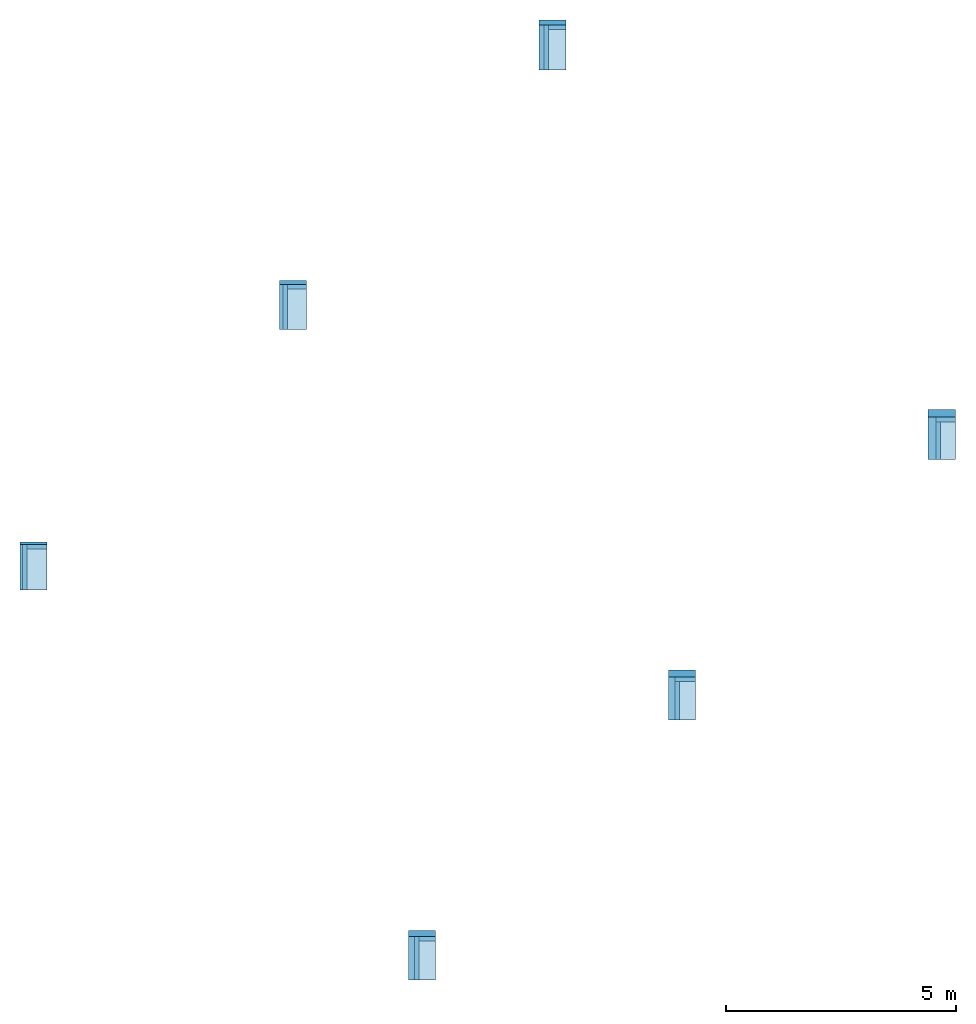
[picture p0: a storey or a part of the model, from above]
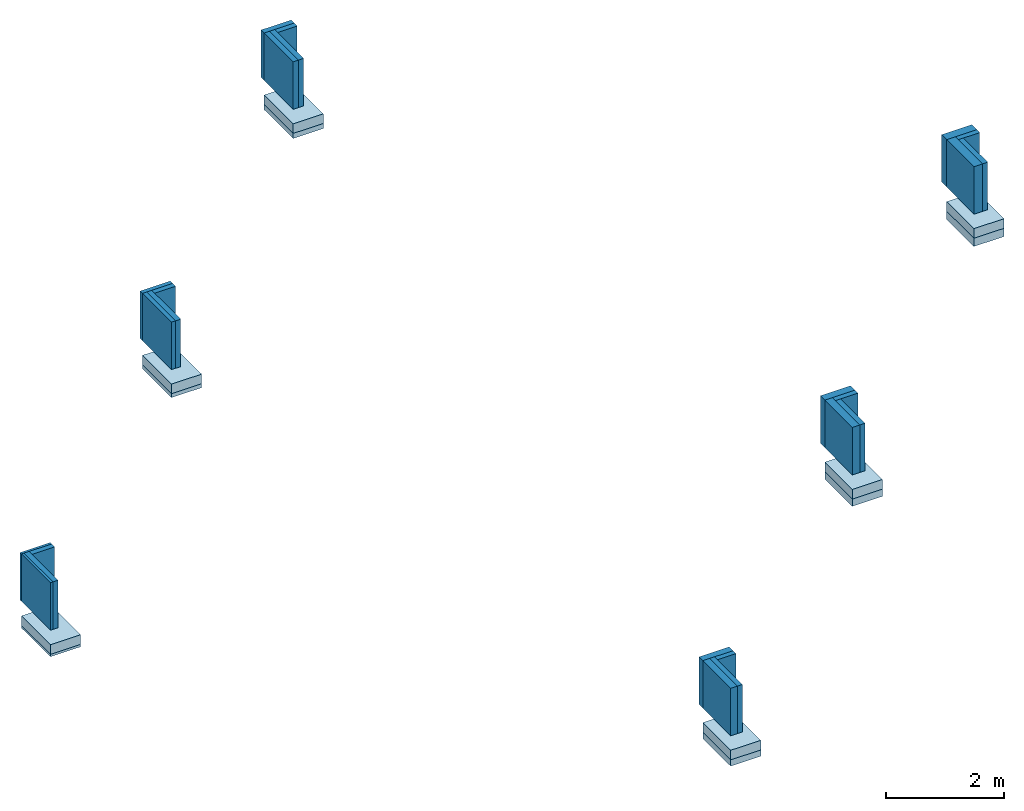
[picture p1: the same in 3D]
Properties of the parts of a building model (IFC2X3), part 1 of 2

# File
Description: ViewDefinition [CoordinationView_V2.0, QuantityTakeOffAddOnView]
File name: 012345
Time: 2019-12-04T13:08:42
Written by: The EXPRESS Data Manager Version 5.02.0100.07 : 28 Aug 2013
Made in: 20190507_1515(x64) - Exporter 17.0.517.0 - Alternate UI 17.15.0.0
Comment: STEP Physical File produced by: The EXPRESS Data Manager Version 5.02.0100.07 : 28 Aug 2013 * Module: EDMstepFileFactory/EDMstandAlone * Creation date: Wed Dec 04 13:08:42 2019 * Host: lt-026 * Database: C:\Users\WF2BF~1.POE\AppData\Local\Temp\{B53F2244-0315-493A-A30E-173DDC3E3202}\ifc * Database version: 5507 * Database creation date: Wed Dec 04 13:08:38 2019 * Schema: IFC2X3 * Model: DataRepository.ifc * Model creation date: Wed Dec 04 13:08:40 2019 * Header model: DataRepository.ifc_HeaderModel * Header model creation date: Wed Dec 04 13:08:40 2019 * EDMuser: sdai-user * EDMgroup: sdai-group * License ID and type: 5605 : Permanent license. Expiry date: * EDMstepFileFactory options: 020000

# IfcProject, 012345
LongName: Cadix Project Naam; Phase: Cadix leeg V2.0

# IfcSite, Default
RefLatitude: 52, 3, 20, 225830; RefLongitude: 5, 6, 28, 692855; RefElevation: 0 mm
Identity Data - Author: Cadix; Organization Name: Cadix
Other - Category: Project Information; Client Name: Vragen? info@cadix.nl; Project Address: Ampèrelaan 1c, 9207 AM Drachten; Project Issue Date: 06-06-2017; Project Name: Cadix Project Naam; Project Number: 012345; Project Status: Cadix leeg V2.0

# IfcBuilding
Pset_BuildingCommon - NumberOfStoreys: 2
Identity Data - Author: Cadix; Organization Name: Cadix
Other - Category: Project Information; Client Name: Vragen? info@cadix.nl; Project Address: Ampèrelaan 1c, 9207 AM Drachten; Project Issue Date: 06-06-2017; Project Name: Cadix Project Naam; Project Number: 012345; Project Status: Cadix leeg V2.0

# IfcBuildingStorey (2)
Dimensions - Computation Height: 0 mm
Identity Data - Structural: no; Building Story: yes; Type Name: niveau
Other - Category: Levels; Family: Level: niveau; Family and Type: Level: niveau; Type: Level: niveau; Type Id: Level: niveau; Family Name: Level
Constraints - Elevation Base: Project Base Point
Graphics - Color: 8421504; Line Pattern: 00_niveau; Line Weight: 1; Symbol: NLRS_00_LAB_niveau bovenkant_gen_cadix: 1.8mm; Symbol at End 1 Default: yes; Symbol at End 2 Default: no
Name | LongName = Name | Elevation (mm) | Constraints, Elevation (mm)
00 begane grond | 00 begane grond | -2.7707e-11 | 0
01 eerste verdieping | 01 eerste verdieping | 985 | 985

# IfcCovering: Compound Ceiling:NLRS_45_CEI_Heraklith Herafoam 105x985x590mm, Compound Ceiling:NLRS_45_CEI_Heraklith Herafoam 105x985x590mm:925877
In: 01 eerste verdieping
PredefinedType: CEILING; Classification: 45.0 (Uniformat); Material: Heraklith® | Herafoam - PIR (0,0215) 55 mm, Heraklith® | Herafoam - PIR (0,0275) 40 mm, Heraklith® | Herafoam - Houtwollaag - 985x590mm 10 mm
Pset_CoveringCommon - Reference: NLRS_45_CEI_Heraklith Herafoam 105x985x590mm; Finish: Heraklith® | Herafoam - Houtwollaag - 985x590mm;; TotalThickness: 105 mm
Pset_ManufacturerTypeInformation - Manufacturer: Knauf Insulation B.V.
BaseQuantities - GrossCeilingArea: 0.58115 m2
Constraints - Room Bounding: yes; Level: Level: 01 eerste verdieping; Height Offset From Level: -105 mm
Dimensions - Area: 0.58115 m2; Perimeter: 3150 mm; Volume: 0.0610207 m3
Other - Category: Ceilings; Family: Compound Ceiling: NLRS_45_CEI_Heraklith Herafoam 105x985x590mm; Family and Type: Compound Ceiling: NLRS_45_CEI_Heraklith Herafoam 105x985x590mm; Type: Compound Ceiling: NLRS_45_CEI_Heraklith Herafoam 105x985x590mm; Type Id: Compound Ceiling: NLRS_45_CEI_Heraklith Herafoam 105x985x590mm; Family Name: Compound Ceiling
Phasing - Phase Created: 1
Analytical Properties - Roughness: 1; Absorptance: 0.1; Heat Transfer Coefficient (U): 0.22577; Thermal mass: 735; Thermal Resistance (R): 4.42929
Construction - Thickness: 105 mm
Graphics - Coarse Scale Fill Color: 0
Identity Data - Type Image: Raster image: Heraklith Herafoam.jpg; Assembly Code: 45.0; brandweerstand: n.v.t; Description: Herafoam - 105mm; DoP: 4010_HERAFOAM; email: customerservice.nl@knaufinsulation.com; geluidsabsorbtie: 0,30; Manufacturer: Knauf Insulation B.V.; Model: Heraklith® | Herafoam is een houtwolcementpaneel gecombineerd met een PIR-plaat.; NLRS_C_Code_Brandklasse: B-s1,d0; NLRS_C_content_creator: Cadix; NLRS_C_content_versie: V1.0; phone: +31(0)162-421245; product URL: https://heraklith.nl/Heraklith-houtwolcementplaten/herafoam; Type Name: NLRS_45_CEI_Heraklith Herafoam 105x985x590mm; URL: www.heraklith.nl; warmteweerstand: 4,10 (m2.K/W)

# IfcCovering: Compound Ceiling:NLRS_45_CEI_Heraklith Herafoam 130x985x590mm, Compound Ceiling:NLRS_45_CEI_Heraklith Herafoam 130x985x590mm:926118
In: 01 eerste verdieping
PredefinedType: CEILING; Classification: 45.0 (Uniformat); Material: Heraklith® | Herafoam - PIR (0,0215) 80 mm, Heraklith® | Herafoam - PIR (0,0275) 40 mm, Heraklith® | Herafoam - Houtwollaag - 985x590mm 10 mm
Pset_CoveringCommon - Reference: NLRS_45_CEI_Heraklith Herafoam 130x985x590mm; Finish: Heraklith® | Herafoam - Houtwollaag - 985x590mm;; TotalThickness: 130 mm
Pset_ManufacturerTypeInformation - Manufacturer: Knauf Insulation B.V.
BaseQuantities - GrossCeilingArea: 0.55755 m2
Constraints - Room Bounding: yes; Level: Level: 01 eerste verdieping; Height Offset From Level: -130 mm
Dimensions - Area: 0.55755 m2; Perimeter: 3070 mm; Volume: 0.0724815 m3
Other - Category: Ceilings; Family: Compound Ceiling: NLRS_45_CEI_Heraklith Herafoam 130x985x590mm; Family and Type: Compound Ceiling: NLRS_45_CEI_Heraklith Herafoam 130x985x590mm; Type: Compound Ceiling: NLRS_45_CEI_Heraklith Herafoam 130x985x590mm; Type Id: Compound Ceiling: NLRS_45_CEI_Heraklith Herafoam 130x985x590mm; Family Name: Compound Ceiling
Phasing - Phase Created: 1
Analytical Properties - Roughness: 1; Absorptance: 0.1; Heat Transfer Coefficient (U): 0.179673; Thermal mass: 810; Thermal Resistance (R): 5.56566
Construction - Thickness: 130 mm
Graphics - Coarse Scale Fill Color: 0
Identity Data - Type Image: Raster image: Heraklith Herafoam.jpg; Assembly Code: 45.0; brandweerstand: n.v.t; Description: Herafoam - 130mm; DoP: 4010_HERAFOAM; email: customerservice.nl@knaufinsulation.com; geluidsabsorbtie: 0,30; Manufacturer: Knauf Insulation B.V.; Model: Heraklith® | Herafoam is een houtwolcementpaneel gecombineerd met een PIR-plaat.; NLRS_C_Code_Brandklasse: B-s1,d0; NLRS_C_content_creator: Cadix; NLRS_C_content_versie: V1.0; phone: +31(0)162-421245; product URL: https://heraklith.nl/Heraklith-houtwolcementplaten/herafoam; Type Name: NLRS_45_CEI_Heraklith Herafoam 130x985x590mm; URL: www.heraklith.nl; warmteweerstand: 5,25 (m2.K/W)

# IfcCovering: Compound Ceiling:NLRS_45_CEI_Heraklith Herafoam 150x985x590mm, Compound Ceiling:NLRS_45_CEI_Heraklith Herafoam 150x985x590mm:926490
In: 01 eerste verdieping
PredefinedType: CEILING; Classification: 45.0 (Uniformat); Material: Heraklith® | Herafoam - PIR (0,0215) 100 mm, Heraklith® | Herafoam - PIR (0,0275) 40 mm, Heraklith® | Herafoam - Houtwollaag - 985x590mm 10 mm
Pset_CoveringCommon - Reference: NLRS_45_CEI_Heraklith Herafoam 150x985x590mm; Finish: Heraklith® | Herafoam - Houtwollaag - 985x590mm;; TotalThickness: 150 mm
Pset_ManufacturerTypeInformation - Manufacturer: Knauf Insulation B.V.
BaseQuantities - GrossCeilingArea: 0.55165 m2
Constraints - Room Bounding: yes; Level: Level: 01 eerste verdieping; Height Offset From Level: -150 mm
Dimensions - Area: 0.55165 m2; Perimeter: 3050 mm; Volume: 0.0827475 m3
Other - Category: Ceilings; Family: Compound Ceiling: NLRS_45_CEI_Heraklith Herafoam 150x985x590mm; Family and Type: Compound Ceiling: NLRS_45_CEI_Heraklith Herafoam 150x985x590mm; Type: Compound Ceiling: NLRS_45_CEI_Heraklith Herafoam 150x985x590mm; Type Id: Compound Ceiling: NLRS_45_CEI_Heraklith Herafoam 150x985x590mm; Family Name: Compound Ceiling
Phasing - Phase Created: 1
Analytical Properties - Roughness: 1; Absorptance: 0.1; Heat Transfer Coefficient (U): 0.154446; Thermal mass: 870; Thermal Resistance (R): 6.47475
Construction - Thickness: 150 mm
Graphics - Coarse Scale Fill Color: 0
Identity Data - Type Image: Raster image: Heraklith Herafoam.jpg; Assembly Code: 45.0; brandweerstand: n.v.t; Description: Herafoam - 150mm; DoP: 4010_HERAFOAM; email: customerservice.nl@knaufinsulation.com; geluidsabsorbtie: 0,30; Manufacturer: Knauf Insulation B.V.; Model: Heraklith® | Herafoam is een houtwolcementpaneel gecombineerd met een PIR-plaat.; NLRS_C_Code_Brandklasse: B-s1,d0; NLRS_C_content_creator: Cadix; NLRS_C_content_versie: V1.0; phone: +31(0)162-421245; product URL: https://heraklith.nl/Heraklith-houtwolcementplaten/herafoam; Type Name: NLRS_45_CEI_Heraklith Herafoam 150x985x590mm; URL: www.heraklith.nl; warmteweerstand: 6,20 (m2.K/W)

# IfcCovering: Compound Ceiling:NLRS_45_CEI_Heraklith Herafoam 170x985x590mm, Compound Ceiling:NLRS_45_CEI_Heraklith Herafoam 170x985x590mm:926819
In: 01 eerste verdieping
PredefinedType: CEILING; Classification: 45.0 (Uniformat); Material: Heraklith® | Herafoam - PIR (0,0215) 120 mm, Heraklith® | Herafoam - PIR (0,0275) 40 mm, Heraklith® | Herafoam - Houtwollaag - 985x590mm 10 mm
Pset_CoveringCommon - Reference: NLRS_45_CEI_Heraklith Herafoam 170x985x590mm; Finish: Heraklith® | Herafoam - Houtwollaag - 985x590mm;; TotalThickness: 170 mm
Pset_ManufacturerTypeInformation - Manufacturer: Knauf Insulation B.V.
BaseQuantities - GrossCeilingArea: 0.54575 m2
Constraints - Room Bounding: yes; Level: Level: 01 eerste verdieping; Height Offset From Level: -170 mm
Dimensions - Area: 0.54575 m2; Perimeter: 3030 mm; Volume: 0.0927775 m3
Other - Category: Ceilings; Family: Compound Ceiling: NLRS_45_CEI_Heraklith Herafoam 170x985x590mm; Family and Type: Compound Ceiling: NLRS_45_CEI_Heraklith Herafoam 170x985x590mm; Type: Compound Ceiling: NLRS_45_CEI_Heraklith Herafoam 170x985x590mm; Type Id: Compound Ceiling: NLRS_45_CEI_Heraklith Herafoam 170x985x590mm; Family Name: Compound Ceiling
Phasing - Phase Created: 1
Analytical Properties - Roughness: 1; Absorptance: 0.1; Heat Transfer Coefficient (U): 0.135431; Thermal mass: 930; Thermal Resistance (R): 7.38384
Construction - Thickness: 170 mm
Graphics - Coarse Scale Fill Color: 0
Identity Data - Type Image: Raster image: Heraklith Herafoam.jpg; Assembly Code: 45.0; brandweerstand: n.v.t; Description: Herafoam - 170mm; DoP: 4010_HERAFOAM; email: customerservice.nl@knaufinsulation.com; geluidsabsorbtie: 0,30; Manufacturer: Knauf Insulation B.V.; Model: Heraklith® | Herafoam is een houtwolcementpaneel gecombineerd met een PIR-plaat.; NLRS_C_Code_Brandklasse: B-s1,d0; NLRS_C_content_creator: Cadix; NLRS_C_content_versie: V1.0; phone: +31(0)162-421245; product URL: https://heraklith.nl/Heraklith-houtwolcementplaten/herafoam; Type Name: NLRS_45_CEI_Heraklith Herafoam 170x985x590mm; URL: www.heraklith.nl; warmteweerstand: 7,10 (m2.K/W)

# IfcCovering: Compound Ceiling:NLRS_45_CEI_Heraklith Herafoam 50x985x590mm, Compound Ceiling:NLRS_45_CEI_Heraklith Herafoam 50x985x590mm:923171
In: 01 eerste verdieping
PredefinedType: CEILING; Classification: 45.0 (Uniformat); Material: Heraklith® | Herafoam - PIR (0,0275) 40 mm, Heraklith® | Herafoam - Houtwollaag - 985x590mm 10 mm
Pset_CoveringCommon - Reference: NLRS_45_CEI_Heraklith Herafoam 50x985x590mm; Finish: Heraklith® | Herafoam - Houtwollaag - 985x590mm;; TotalThickness: 50 mm
Pset_ManufacturerTypeInformation - Manufacturer: Knauf Insulation B.V.
BaseQuantities - GrossCeilingArea: 0.58115 m2
Constraints - Room Bounding: yes; Height Offset From Level: -50 mm; Level: Level: 01 eerste verdieping
Dimensions - Area: 0.58115 m2; Perimeter: 3150 mm; Volume: 0.0290575 m3
Other - Category: Ceilings; Family: Compound Ceiling: NLRS_45_CEI_Heraklith Herafoam 50x985x590mm; Family and Type: Compound Ceiling: NLRS_45_CEI_Heraklith Herafoam 50x985x590mm; Type: Compound Ceiling: NLRS_45_CEI_Heraklith Herafoam 50x985x590mm; Type Id: Compound Ceiling: NLRS_45_CEI_Heraklith Herafoam 50x985x590mm; Family Name: Compound Ceiling
Phasing - Phase Created: 1
Analytical Properties - Roughness: 1; Absorptance: 0.1; Heat Transfer Coefficient (U): 0.518325; Thermal mass: 570; Thermal Resistance (R): 1.92929
Construction - Thickness: 50 mm
Graphics - Coarse Scale Fill Color: 0
Identity Data - Type Image: Raster image: Heraklith Herafoam.jpg; Assembly Code: 45.0; brandweerstand: n.v.t; Description: Herafoam - 50mm; DoP: 4010_HERAFOAM; email: customerservice.nl@knaufinsulation.com; geluidsabsorbtie: 0,30; Manufacturer: Knauf Insulation B.V.; Model: Heraklith® | Herafoam is een houtwolcementpaneel gecombineerd met een PIR-plaat.; NLRS_C_Code_Brandklasse: B-s1,d0; NLRS_C_content_creator: Cadix; NLRS_C_content_versie: V1.0; phone: +31(0)162-421245; product URL: https://heraklith.nl/Heraklith-houtwolcementplaten/herafoam; Type Name: NLRS_45_CEI_Heraklith Herafoam 50x985x590mm; URL: www.heraklith.nl; warmteweerstand: 1,55 (m2.K/W)

# IfcCovering: Compound Ceiling:NLRS_45_CEI_Heraklith Herafoam 80x985x590mm, Compound Ceiling:NLRS_45_CEI_Heraklith Herafoam 80x985x590mm:925586
In: 01 eerste verdieping
PredefinedType: CEILING; Classification: 45.0 (Uniformat); Material: Heraklith® | Herafoam - PIR (0,0222) 30 mm, Heraklith® | Herafoam - PIR (0,0275) 40 mm, Heraklith® | Herafoam - Houtwollaag - 985x590mm 10 mm
Pset_CoveringCommon - Reference: NLRS_45_CEI_Heraklith Herafoam 80x985x590mm; Finish: Heraklith® | Herafoam - Houtwollaag - 985x590mm;; TotalThickness: 80 mm
Pset_ManufacturerTypeInformation - Manufacturer: Knauf Insulation B.V.
BaseQuantities - GrossCeilingArea: 0.58115 m2
Constraints - Room Bounding: yes; Height Offset From Level: -80 mm; Level: Level: 01 eerste verdieping
Dimensions - Area: 0.58115 m2; Perimeter: 3150 mm; Volume: 0.046492 m3
Other - Category: Ceilings; Family: Compound Ceiling: NLRS_45_CEI_Heraklith Herafoam 80x985x590mm; Family and Type: Compound Ceiling: NLRS_45_CEI_Heraklith Herafoam 80x985x590mm; Type: Compound Ceiling: NLRS_45_CEI_Heraklith Herafoam 80x985x590mm; Type Id: Compound Ceiling: NLRS_45_CEI_Heraklith Herafoam 80x985x590mm; Family Name: Compound Ceiling
Phasing - Phase Created: 1
Analytical Properties - Roughness: 1; Absorptance: 0.1; Heat Transfer Coefficient (U): 0.303681; Thermal mass: 660; Thermal Resistance (R): 3.29293
Construction - Thickness: 80 mm
Graphics - Coarse Scale Fill Color: 0
Identity Data - Type Image: Raster image: Heraklith Herafoam.jpg; Assembly Code: 45.0; brandweerstand: n.v.t; Description: Herafoam - 80mm; DoP: 4010_HERAFOAM; email: customerservice.nl@knaufinsulation.com; geluidsabsorbtie: 0,30; Manufacturer: Knauf Insulation B.V.; Model: Heraklith® | Herafoam is een houtwolcementpaneel gecombineerd met een PIR-plaat.; NLRS_C_Code_Brandklasse: B-s1,d0; NLRS_C_content_creator: Cadix; NLRS_C_content_versie: V1.0; phone: +31(0)162-421245; product URL: https://heraklith.nl/Heraklith-houtwolcementplaten/herafoam; Type Name: NLRS_45_CEI_Heraklith Herafoam 80x985x590mm; URL: www.heraklith.nl; warmteweerstand: 2,90 (m2.K/W)

# IfcSlab: Floor:Generic 200mm (12)
PredefinedType: FLOOR; Material: Concrete, Precast Panels 200 mm
Pset_SlabCommon - LoadBearing: yes; PitchAngle: 0 deg; IsExternal: no; Reference: Generic 200mm; ThermalTransmittance: 5.23 kg/K/s3
BaseQuantities - Width: 200 mm
Constraints - Related to Mass: no; Room Bounding: yes
Dimensions - Thickness: 200 mm
Other - Category: Floors; Family: Floor: Generic 200mm; Family and Type: Floor: Generic 200mm; Type: Floor: Generic 200mm; Type Id: Floor: Generic 200mm; Family Name: Floor
Phasing - Phase Created: 1
Structural - Enable Analytical Model: no; Structural: no
Analytical Properties - Roughness: 3; Absorptance: 0.7; Heat Transfer Coefficient (U): 5.23; Thermal mass: 302220; Thermal Resistance (R): 0.191205
Construction - Function: Interior; Default Thickness: 200 mm
Graphics - Coarse Scale Fill Color: 0
Identity Data - Type Name: Generic 200mm
Materials and Finishes - Structural Material: Concrete, Precast Panels
Name (Floor:Generic 200mm:...) | In | GrossArea (m2) = Area (m2) | GrossVolume (m3) | BaseQuantities, Perimeter (mm) = Dimensions, Perimeter (mm) | Level | Height Offset From Level (mm) | Elevation at Bottom (mm) | Elevation at Top (mm) | Volume (m3)
929235 | 01 eerste verdieping | 0.58115 | 116.23 | 3150 | Level: 01 eerste verdieping | 200 | 985 | 1185 | 0.11623
929303 | 01 eerste verdieping | 0.58115 | 116.23 | 3150 | Level: 01 eerste verdieping | 200 | 985 | 1185 | 0.11623
929332 | 01 eerste verdieping | 0.58115 | 116.23 | 3150 | Level: 01 eerste verdieping | 200 | 985 | 1185 | 0.11623
929359 | 01 eerste verdieping | 0.54575 | 109.15 | 3030 | Level: 01 eerste verdieping | 200 | 985 | 1185 | 0.10915
929386 | 01 eerste verdieping | 0.55165 | 110.33 | 3050 | Level: 01 eerste verdieping | 200 | 985 | 1185 | 0.11033
929415 | 01 eerste verdieping | 0.55755 | 111.51 | 3070 | Level: 01 eerste verdieping | 200 | 985 | 1185 | 0.11151
930300 | 00 begane grond | 0.58115 | 116.23 | 3150 | Level: 00 begane grond | -300 | -500 | -300 | 0.11623
930329 | 00 begane grond | 0.58115 | 116.23 | 3150 | Level: 00 begane grond | -300 | -500 | -300 | 0.11623
930358 | 00 begane grond | 0.58115 | 116.23 | 3150 | Level: 00 begane grond | -300 | -500 | -300 | 0.11623
930387 | 00 begane grond | 0.54575 | 109.15 | 3030 | Level: 00 begane grond | -300 | -500 | -300 | 0.10915
930416 | 00 begane grond | 0.55165 | 110.33 | 3050 | Level: 00 begane grond | -300 | -500 | -300 | 0.11033
930446 | 00 begane grond | 0.55755 | 111.51 | 3070 | Level: 00 begane grond | -300 | -500 | -300 | 0.11151

# IfcSlab: Floor:NLRS_23_FL_Heraklith Herafoam 105x985x590mm, Floor:NLRS_23_FL_Heraklith Herafoam 105x985x590mm:925716
In: 00 begane grond
PredefinedType: FLOOR; Classification: 23.0 (Uniformat); Material: Heraklith® | Herafoam - PIR (0,0215) 55 mm, Heraklith® | Herafoam - PIR (0,0275) 40 mm, Heraklith® | Herafoam - Houtwollaag - 985x590mm 10 mm
Pset_SlabCommon - IsExternal: yes; LoadBearing: yes; PitchAngle: 0 deg; Reference: NLRS_23_FL_Heraklith Herafoam 105x985x590mm; ThermalTransmittance: 0.22577 kg/K/s3
Pset_ManufacturerTypeInformation - Manufacturer: Knauf Insulation B.V.
BaseQuantities - GrossArea: 0.58115 m2; GrossVolume: 61.0208 m3; Perimeter: 3150 mm; Width: 105 mm
Constraints - Level: Level: 00 begane grond; Related to Mass: no; Room Bounding: yes; Height Offset From Level: -500 mm
Dimensions - Area: 0.58115 m2; Elevation at Bottom: -605 mm; Elevation at Top: -500 mm; Perimeter: 3150 mm; Thickness: 105 mm; Volume: 0.0610208 m3
Other - Category: Floors; Family: Floor: NLRS_23_FL_Heraklith Herafoam 105x985x590mm; Family and Type: Floor: NLRS_23_FL_Heraklith Herafoam 105x985x590mm; Type: Floor: NLRS_23_FL_Heraklith Herafoam 105x985x590mm; Type Id: Floor: NLRS_23_FL_Heraklith Herafoam 105x985x590mm; Family Name: Floor
Phasing - Phase Created: 1
Structural - Enable Analytical Model: no; Structural: no
Analytical Properties - Roughness: 1; Absorptance: 0.1; Heat Transfer Coefficient (U): 0.22577; Thermal mass: 735; Thermal Resistance (R): 4.42929
Construction - Function: Exterior; Default Thickness: 105 mm
Graphics - Coarse Scale Fill Color: 0
Identity Data - Type Image: Raster image: Heraklith Herafoam.jpg; Assembly Code: 23.0; brandweerstand: n.v.t; Description: Herafoam - 105mm; DoP: 4010_HERAFOAM; email: customerservice.nl@knaufinsulation.com; geluidsabsorbtie: 0,30; Manufacturer: Knauf Insulation B.V.; Model: Heraklith® | Herafoam is een houtwolcementpaneel gecombineerd met een PIR-plaat.; NLRS_C_Code_Brandklasse: B-s1,d0; NLRS_C_content_creator: Cadix; NLRS_C_content_versie: V1.0; phone: +31(0)162-421245; product URL: https://heraklith.nl/Heraklith-houtwolcementplaten/herafoam; Type Name: NLRS_23_FL_Heraklith Herafoam 105x985x590mm; URL: www.heraklith.nl; warmteweerstand: 4,10 (m2.K/W)

# IfcSlab: Floor:NLRS_23_FL_Heraklith Herafoam 130x985x590mm, Floor:NLRS_23_FL_Heraklith Herafoam 130x985x590mm:926109
In: 00 begane grond
PredefinedType: FLOOR; Classification: 23.0 (Uniformat); Material: Heraklith® | Herafoam - PIR (0,0215) 80 mm, Heraklith® | Herafoam - PIR (0,0275) 40 mm, Heraklith® | Herafoam - Houtwollaag - 985x590mm 10 mm
Pset_SlabCommon - IsExternal: yes; LoadBearing: yes; PitchAngle: 0 deg; Reference: NLRS_23_FL_Heraklith Herafoam 130x985x590mm; ThermalTransmittance: 0.179673 kg/K/s3
Pset_ManufacturerTypeInformation - Manufacturer: Knauf Insulation B.V.
BaseQuantities - GrossArea: 0.55755 m2; GrossVolume: 72.4815 m3; Perimeter: 3070 mm; Width: 130 mm
Constraints - Related to Mass: no; Room Bounding: yes; Height Offset From Level: -500 mm; Level: Level: 00 begane grond
Dimensions - Area: 0.55755 m2; Elevation at Bottom: -630 mm; Elevation at Top: -500 mm; Perimeter: 3070 mm; Thickness: 130 mm; Volume: 0.0724815 m3
Other - Category: Floors; Family: Floor: NLRS_23_FL_Heraklith Herafoam 130x985x590mm; Family and Type: Floor: NLRS_23_FL_Heraklith Herafoam 130x985x590mm; Type: Floor: NLRS_23_FL_Heraklith Herafoam 130x985x590mm; Type Id: Floor: NLRS_23_FL_Heraklith Herafoam 130x985x590mm; Family Name: Floor
Phasing - Phase Created: 1
Structural - Enable Analytical Model: no; Structural: no
Analytical Properties - Roughness: 1; Absorptance: 0.1; Heat Transfer Coefficient (U): 0.179673; Thermal mass: 810; Thermal Resistance (R): 5.56566
Construction - Function: Exterior; Default Thickness: 130 mm
Graphics - Coarse Scale Fill Color: 0
Identity Data - Type Image: Raster image: Heraklith Herafoam.jpg; Assembly Code: 23.0; brandweerstand: n.v.t; Description: Herafoam - 130mm; DoP: 4010_HERAFOAM; email: customerservice.nl@knaufinsulation.com; geluidsabsorbtie: 0,30; Manufacturer: Knauf Insulation B.V.; Model: Heraklith® | Herafoam is een houtwolcementpaneel gecombineerd met een PIR-plaat.; NLRS_C_Code_Brandklasse: B-s1,d0; NLRS_C_content_creator: Cadix; NLRS_C_content_versie: V1.0; phone: +31(0)162-421245; product URL: https://heraklith.nl/Heraklith-houtwolcementplaten/herafoam; Type Name: NLRS_23_FL_Heraklith Herafoam 130x985x590mm; URL: www.heraklith.nl; warmteweerstand: 5,25 (m2.K/W)

# IfcSlab: Floor:NLRS_23_FL_Heraklith Herafoam 150x985x590mm, Floor:NLRS_23_FL_Heraklith Herafoam 150x985x590mm:926482
In: 00 begane grond
PredefinedType: FLOOR; Classification: 23.0 (Uniformat); Material: Heraklith® | Herafoam - PIR (0,0215) 100 mm, Heraklith® | Herafoam - PIR (0,0275) 40 mm, Heraklith® | Herafoam - Houtwollaag - 985x590mm 10 mm
Pset_SlabCommon - IsExternal: yes; LoadBearing: yes; PitchAngle: 0 deg; Reference: NLRS_23_FL_Heraklith Herafoam 150x985x590mm; ThermalTransmittance: 0.154446 kg/K/s3
Pset_ManufacturerTypeInformation - Manufacturer: Knauf Insulation B.V.
BaseQuantities - GrossArea: 0.55165 m2; GrossVolume: 82.7475 m3; Perimeter: 3050 mm; Width: 150 mm
Constraints - Level: Level: 00 begane grond; Related to Mass: no; Room Bounding: yes; Height Offset From Level: -500 mm
Dimensions - Area: 0.55165 m2; Elevation at Bottom: -650 mm; Elevation at Top: -500 mm; Perimeter: 3050 mm; Thickness: 150 mm; Volume: 0.0827475 m3
Other - Category: Floors; Family: Floor: NLRS_23_FL_Heraklith Herafoam 150x985x590mm; Family and Type: Floor: NLRS_23_FL_Heraklith Herafoam 150x985x590mm; Type: Floor: NLRS_23_FL_Heraklith Herafoam 150x985x590mm; Type Id: Floor: NLRS_23_FL_Heraklith Herafoam 150x985x590mm; Family Name: Floor
Phasing - Phase Created: 1
Structural - Enable Analytical Model: no; Structural: no
Analytical Properties - Roughness: 1; Absorptance: 0.1; Heat Transfer Coefficient (U): 0.154446; Thermal mass: 870; Thermal Resistance (R): 6.47475
Construction - Function: Exterior; Default Thickness: 150 mm
Graphics - Coarse Scale Fill Color: 0
Identity Data - Type Image: Raster image: Heraklith Herafoam.jpg; Assembly Code: 23.0; brandweerstand: n.v.t; Description: Herafoam - 150mm; DoP: 4010_HERAFOAM; email: customerservice.nl@knaufinsulation.com; geluidsabsorbtie: 0,30; Manufacturer: Knauf Insulation B.V.; Model: Heraklith® | Herafoam is een houtwolcementpaneel gecombineerd met een PIR-plaat.; NLRS_C_Code_Brandklasse: B-s1,d0; NLRS_C_content_creator: Cadix; NLRS_C_content_versie: V1.0; phone: +31(0)162-421245; product URL: https://heraklith.nl/Heraklith-houtwolcementplaten/herafoam; Type Name: NLRS_23_FL_Heraklith Herafoam 150x985x590mm; URL: www.heraklith.nl; warmteweerstand: 6,20 (m2.K/W)

# IfcSlab: Floor:NLRS_23_FL_Heraklith Herafoam 170x985x590mm, Floor:NLRS_23_FL_Heraklith Herafoam 170x985x590mm:926812
In: 00 begane grond
PredefinedType: FLOOR; Classification: 23.0 (Uniformat); Material: Heraklith® | Herafoam - PIR (0,0215) 120 mm, Heraklith® | Herafoam - PIR (0,0275) 40 mm, Heraklith® | Herafoam - Houtwollaag - 985x590mm 10 mm
Pset_SlabCommon - IsExternal: yes; LoadBearing: yes; PitchAngle: 0 deg; Reference: NLRS_23_FL_Heraklith Herafoam 170x985x590mm; ThermalTransmittance: 0.135431 kg/K/s3
Pset_ManufacturerTypeInformation - Manufacturer: Knauf Insulation B.V.
BaseQuantities - GrossArea: 0.54575 m2; GrossVolume: 92.7775 m3; Perimeter: 3030 mm; Width: 170 mm
Constraints - Related to Mass: no; Room Bounding: yes; Level: Level: 00 begane grond; Height Offset From Level: -500 mm
Dimensions - Area: 0.54575 m2; Elevation at Bottom: -670 mm; Elevation at Top: -500 mm; Perimeter: 3030 mm; Thickness: 170 mm; Volume: 0.0927775 m3
Other - Category: Floors; Family: Floor: NLRS_23_FL_Heraklith Herafoam 170x985x590mm; Family and Type: Floor: NLRS_23_FL_Heraklith Herafoam 170x985x590mm; Type: Floor: NLRS_23_FL_Heraklith Herafoam 170x985x590mm; Type Id: Floor: NLRS_23_FL_Heraklith Herafoam 170x985x590mm; Family Name: Floor
Phasing - Phase Created: 1
Structural - Enable Analytical Model: no; Structural: no
Analytical Properties - Roughness: 1; Absorptance: 0.1; Heat Transfer Coefficient (U): 0.135431; Thermal mass: 930; Thermal Resistance (R): 7.38384
Construction - Function: Exterior; Default Thickness: 170 mm
Graphics - Coarse Scale Fill Color: 0
Identity Data - Type Image: Raster image: Heraklith Herafoam.jpg; Assembly Code: 23.0; brandweerstand: n.v.t; Description: Herafoam - 170mm; DoP: 4010_HERAFOAM; email: customerservice.nl@knaufinsulation.com; geluidsabsorbtie: 0,30; Manufacturer: Knauf Insulation B.V.; Model: Heraklith® | Herafoam is een houtwolcementpaneel gecombineerd met een PIR-plaat.; NLRS_C_Code_Brandklasse: B-s1,d0; NLRS_C_content_creator: Cadix; NLRS_C_content_versie: V1.0; phone: +31(0)162-421245; product URL: https://heraklith.nl/Heraklith-houtwolcementplaten/herafoam; Type Name: NLRS_23_FL_Heraklith Herafoam 170x985x590mm; URL: www.heraklith.nl; warmteweerstand: 7,10 (m2.K/W)

# IfcSlab: Floor:NLRS_23_FL_Heraklith Herafoam 50x985x590mm, Floor:NLRS_23_FL_Heraklith Herafoam 50x985x590mm:905862
In: 00 begane grond
PredefinedType: FLOOR; Classification: 23.0 (Uniformat); Material: Heraklith® | Herafoam - PIR (0,0215) 40 mm, Heraklith® | Herafoam - Houtwollaag - 985x590mm 10 mm
Pset_SlabCommon - Reference: NLRS_23_FL_Heraklith Herafoam 50x985x590mm; IsExternal: yes; LoadBearing: yes; ThermalTransmittance: 0.518325 kg/K/s3; PitchAngle: 0 deg
Pset_ManufacturerTypeInformation - Manufacturer: Knauf Insulation B.V.
BaseQuantities - GrossArea: 0.58115 m2; GrossVolume: 29.0575 m3; Perimeter: 3150 mm; Width: 50 mm
Constraints - Height Offset From Level: -500 mm; Level: Level: 00 begane grond; Related to Mass: no; Room Bounding: yes
Dimensions - Area: 0.58115 m2; Elevation at Bottom: -550 mm; Elevation at Top: -500 mm; Perimeter: 3150 mm; Thickness: 50 mm; Volume: 0.0290575 m3
Other - Category: Floors; Family: Floor: NLRS_23_FL_Heraklith Herafoam 50x985x590mm; Family and Type: Floor: NLRS_23_FL_Heraklith Herafoam 50x985x590mm; Type: Floor: NLRS_23_FL_Heraklith Herafoam 50x985x590mm; Type Id: Floor: NLRS_23_FL_Heraklith Herafoam 50x985x590mm; Family Name: Floor
Phasing - Phase Created: 1
Structural - Enable Analytical Model: no; Structural: no
Analytical Properties - Absorptance: 0.1; Heat Transfer Coefficient (U): 0.518325; Roughness: 1; Thermal mass: 570; Thermal Resistance (R): 1.92929
Construction - Default Thickness: 50 mm; Function: Exterior
Graphics - Coarse Scale Fill Color: 0
Identity Data - Assembly Code: 23.0; brandweerstand: n.v.t; Description: Herafoam - 50mm; DoP: 4010_HERAFOAM; email: customerservice.nl@knaufinsulation.com; geluidsabsorbtie: 0,30; Manufacturer: Knauf Insulation B.V.; Model: Heraklith® | Herafoam is een houtwolcementpaneel gecombineerd met een PIR-plaat.; NLRS_C_Code_Brandklasse: B-s1,d0; NLRS_C_content_creator: Cadix; NLRS_C_content_versie: V1.0; phone: +31(0)162-421245; product URL: https://heraklith.nl/Heraklith-houtwolcementplaten/herafoam; Type Image: Raster image: Heraklith Herafoam.jpg; Type Name: NLRS_23_FL_Heraklith Herafoam 50x985x590mm; URL: www.heraklith.nl; warmteweerstand: 1,55 (m2.K/W)

# IfcSlab: Floor:NLRS_23_FL_Heraklith Herafoam 80x985x590mm, Floor:NLRS_23_FL_Heraklith Herafoam 80x985x590mm:925188
In: 00 begane grond
PredefinedType: FLOOR; Classification: 23.0 (Uniformat); Material: Heraklith® | Herafoam - PIR (0,0222) 30 mm, Heraklith® | Herafoam - PIR (0,0275) 40 mm, Heraklith® | Herafoam - Houtwollaag - 985x590mm 10 mm
Pset_SlabCommon - IsExternal: yes; LoadBearing: yes; PitchAngle: 0 deg; Reference: NLRS_23_FL_Heraklith Herafoam 80x985x590mm; ThermalTransmittance: 0.303681 kg/K/s3
Pset_ManufacturerTypeInformation - Manufacturer: Knauf Insulation B.V.
BaseQuantities - GrossArea: 0.58115 m2; GrossVolume: 46.492 m3; Perimeter: 3150 mm; Width: 80 mm
Constraints - Level: Level: 00 begane grond; Related to Mass: no; Room Bounding: yes; Height Offset From Level: -500 mm
Dimensions - Area: 0.58115 m2; Elevation at Bottom: -580 mm; Elevation at Top: -500 mm; Perimeter: 3150 mm; Thickness: 80 mm; Volume: 0.046492 m3
Other - Category: Floors; Family: Floor: NLRS_23_FL_Heraklith Herafoam 80x985x590mm; Family and Type: Floor: NLRS_23_FL_Heraklith Herafoam 80x985x590mm; Type: Floor: NLRS_23_FL_Heraklith Herafoam 80x985x590mm; Type Id: Floor: NLRS_23_FL_Heraklith Herafoam 80x985x590mm; Family Name: Floor
Phasing - Phase Created: 1
Structural - Enable Analytical Model: no; Structural: no
Analytical Properties - Roughness: 1; Absorptance: 0.1; Heat Transfer Coefficient (U): 0.303681; Thermal mass: 660; Thermal Resistance (R): 3.29293
Construction - Function: Exterior; Default Thickness: 80 mm
Graphics - Coarse Scale Fill Color: 0
Identity Data - Type Image: Raster image: Heraklith Herafoam.jpg; Assembly Code: 23.0; brandweerstand: n.v.t; Description: Herafoam - 80mm; DoP: 4010_HERAFOAM; email: customerservice.nl@knaufinsulation.com; geluidsabsorbtie: 0,30; Manufacturer: Knauf Insulation B.V.; Model: Heraklith® | Herafoam is een houtwolcementpaneel gecombineerd met een PIR-plaat.; NLRS_C_Code_Brandklasse: B-s1,d0; NLRS_C_content_creator: Cadix; NLRS_C_content_versie: V1.0; phone: +31(0)162-421245; product URL: https://heraklith.nl/Heraklith-houtwolcementplaten/herafoam; Type Name: NLRS_23_FL_Heraklith Herafoam 80x985x590mm; URL: www.heraklith.nl; warmteweerstand: 2,90 (m2.K/W)

# IfcWallStandardCase: Basic Wall:Generic_100mm (12)
In: 00 begane grond
Type - PredefinedType: STANDARD; Material: Concrete, Precast Panels 100 mm
Type - Analytical Properties - Absorptance: 0.7; Heat Transfer Coefficient (U): 10.46; Roughness: 3; Thermal mass: 151110; Thermal Resistance (R): 0.0956023
Type - Construction - Function: Exterior; Wrapping at Inserts: Do not wrap; Width: 100 mm
Type - Graphics - Coarse Scale Fill Color: 0
Type - Identity Data - Type Name: Generic_100mm
Type - Materials and Finishes - Structural Material: Concrete, Precast Panels
Type - Other - Category: Walls; Family Name: Basic Wall
BaseQuantities - Height: 985 mm; Width: 100 mm
Constraints - Related to Mass: no; Room Bounding: yes; Base Constraint: Level: 00 begane grond; Base Extension Distance: 0 mm; Base is Attached: no; Base Offset: 0 mm; Top Constraint: Level: 01 eerste verdieping; Top Extension Distance: 0 mm; Top is Attached: no; Top Offset: 0 mm; Location Line: Finish Face: Exterior; Unconnected Height: 985 mm
Other - Family: Basic Wall: Generic_100mm; Family and Type: Basic Wall: Generic_100mm; Type: Basic Wall: Generic_100mm; Type Id: Basic Wall: Generic_100mm
Phasing - Phase Created: 1
Structural - Enable Analytical Model: no; Structural: no; Structural Usage: Non-bearing
Pset_WallCommon - IsExternal: yes; LoadBearing: no; ExtendToStructure: no; Reference: Generic_100mm; ThermalTransmittance: 10.46 kg/K/s3
Name (Basic Wall:Generic_100mm:...) | BaseQuantities, Length (mm) | GrossFootprintArea (m2) | GrossSideArea (m2) = Area (m2) | GrossVolume (m3) = Volume (m3) | Dimensions, Length (mm)
928912 | 985 | 0.0985 | 0.970225 | 0.0970225 | 935
928976 | 440 | 0.044 | 0.4334 | 0.04334 | 490
929523 | 985 | 0.0985 | 0.970225 | 0.0970225 | 935
929576 | 410 | 0.041 | 0.40385 | 0.040385 | 460
929639 | 985 | 0.0985 | 0.970225 | 0.0970225 | 935
929706 | 385 | 0.0385 | 0.379225 | 0.0379225 | 435
929774 | 825 | 0.0825 | 0.812625 | 0.0812625 | 875
929814 | 420 | 0.042 | 0.4137 | 0.04137 | 370
929946 | 835 | 0.0835 | 0.822475 | 0.0822475 | 885
930050 | 440 | 0.044 | 0.4334 | 0.04334 | 390
930212 | 945 | 0.0945 | 0.930825 | 0.0930825 | 895
930267 | 360 | 0.036 | 0.3546 | 0.03546 | 410

# IfcWallStandardCase: Basic Wall:NLRS_41_WA_Heraklith Herafoam 105x985x590mm, Basic Wall:NLRS_41_WA_Heraklith Herafoam 105x985x590mm:925874
In: 00 begane grond
Type - PredefinedType: STANDARD; Material: Heraklith® | Herafoam - PIR (0,0215) 55 mm, Heraklith® | Herafoam - PIR (0,0275) 40 mm, Heraklith® | Herafoam - Houtwollaag - 985x590mm 10 mm
Type - Analytical Properties - Roughness: 1; Absorptance: 0.1; Heat Transfer Coefficient (U): 0.22577; Thermal mass: 735; Thermal Resistance (R): 4.42929
Type - Construction - Function: Exterior; Wrapping at Inserts: Do not wrap; Width: 105 mm
Type - Graphics - Coarse Scale Fill Color: 0; Coarse Scale Fill Pattern: Solid fill
Type - Identity Data - Type Image: Raster image: Heraklith Herafoam.jpg; Assembly Code: 41.10; brandweerstand: n.v.t; Description: Herafoam - 105mm; DoP: 4010_HERAFOAM; email: customerservice.nl@knaufinsulation.com; geluidsabsorbtie: 0,30; Manufacturer: Knauf Insulation B.V.; Model: Heraklith® | Herafoam is een houtwolcementpaneel gecombineerd met een PIR-plaat.; NLRS_C_Code_Brandklasse: B-s1,d0; NLRS_C_content_creator: Cadix; NLRS_C_content_versie: V1.0; phone: +31(0)162-421245; product URL: https://heraklith.nl/Heraklith-houtwolcementplaten/herafoam; Type Name: NLRS_41_WA_Heraklith Herafoam 105x985x590mm; URL: www.heraklith.nl; warmteweerstand: 4,10 (m2.K/W)
Type - Other - Category: Walls; Family Name: Basic Wall
Classification: 41.10 (Uniformat)
BaseQuantities - Height: 985 mm; Length: 590 mm; Width: 105 mm; GrossFootprintArea: 0.06195 m2; GrossSideArea: 0.58115 m2; GrossVolume: 0.0610208 m3
Constraints - Related to Mass: no; Room Bounding: yes; Base Constraint: Level: 00 begane grond; Base Extension Distance: 0 mm; Base is Attached: no; Base Offset: 0 mm; Location Line: Wall Centerline; Top Constraint: Level: 01 eerste verdieping; Top Extension Distance: 0 mm; Top is Attached: no; Top Offset: 0 mm; Unconnected Height: 985 mm
Dimensions - Area: 0.58115 m2; Length: 590 mm; Volume: 0.0610208 m3
Other - Family: Basic Wall: NLRS_41_WA_Heraklith Herafoam 105x985x590mm; Family and Type: Basic Wall: NLRS_41_WA_Heraklith Herafoam 105x985x590mm; Type: Basic Wall: NLRS_41_WA_Heraklith Herafoam 105x985x590mm; Type Id: Basic Wall: NLRS_41_WA_Heraklith Herafoam 105x985x590mm
Phasing - Phase Created: 1
Structural - Enable Analytical Model: no; Structural: no; Structural Usage: Non-bearing
Pset_WallCommon - IsExternal: yes; LoadBearing: no; ExtendToStructure: no; Reference: NLRS_41_WA_Heraklith Herafoam 105x985x590mm; ThermalTransmittance: 0.22577 kg/K/s3
Pset_ManufacturerTypeInformation - Manufacturer: Knauf Insulation B.V.

# IfcWallStandardCase: Basic Wall:NLRS_41_WA_Heraklith Herafoam 130x985x590mm, Basic Wall:NLRS_41_WA_Heraklith Herafoam 130x985x590mm:926306
In: 00 begane grond
Type - PredefinedType: STANDARD; Material: Heraklith® | Herafoam - PIR (0,0215) 80 mm, Heraklith® | Herafoam - PIR (0,0275) 40 mm, Heraklith® | Herafoam - Houtwollaag - 985x590mm 10 mm
Type - Analytical Properties - Roughness: 1; Absorptance: 0.1; Heat Transfer Coefficient (U): 0.179673; Thermal mass: 810; Thermal Resistance (R): 5.56566
Type - Construction - Function: Exterior; Wrapping at Inserts: Do not wrap; Width: 130 mm
Type - Graphics - Coarse Scale Fill Color: 0; Coarse Scale Fill Pattern: Solid fill
Type - Identity Data - Type Image: Raster image: Heraklith Herafoam.jpg; Assembly Code: 41.10; brandweerstand: n.v.t; Description: Herafoam - 130mm; DoP: 4010_HERAFOAM; email: customerservice.nl@knaufinsulation.com; geluidsabsorbtie: 0,30; Manufacturer: Knauf Insulation B.V.; Model: Heraklith® | Herafoam is een houtwolcementpaneel gecombineerd met een PIR-plaat.; NLRS_C_Code_Brandklasse: B-s1,d0; NLRS_C_content_creator: Cadix; NLRS_C_content_versie: V1.0; phone: +31(0)162-421245; product URL: https://heraklith.nl/Heraklith-houtwolcementplaten/herafoam; Type Name: NLRS_41_WA_Heraklith Herafoam 130x985x590mm; URL: www.heraklith.nl; warmteweerstand: 5,25 (m2.K/W)
Type - Other - Category: Walls; Family Name: Basic Wall
Classification: 41.10 (Uniformat)
BaseQuantities - Height: 985 mm; Length: 590 mm; Width: 130 mm; GrossFootprintArea: 0.0767 m2; GrossSideArea: 0.58115 m2; GrossVolume: 0.0755495 m3
Constraints - Related to Mass: no; Room Bounding: yes; Base Constraint: Level: 00 begane grond; Base Extension Distance: 0 mm; Base is Attached: no; Base Offset: 0 mm; Location Line: Wall Centerline; Top Constraint: Level: 01 eerste verdieping; Top Extension Distance: 0 mm; Top is Attached: no; Top Offset: 0 mm; Unconnected Height: 985 mm
Dimensions - Area: 0.58115 m2; Length: 590 mm; Volume: 0.0755495 m3
Other - Family: Basic Wall: NLRS_41_WA_Heraklith Herafoam 130x985x590mm; Family and Type: Basic Wall: NLRS_41_WA_Heraklith Herafoam 130x985x590mm; Type: Basic Wall: NLRS_41_WA_Heraklith Herafoam 130x985x590mm; Type Id: Basic Wall: NLRS_41_WA_Heraklith Herafoam 130x985x590mm
Phasing - Phase Created: 1
Structural - Enable Analytical Model: no; Structural: no; Structural Usage: Non-bearing
Pset_WallCommon - IsExternal: yes; LoadBearing: no; ExtendToStructure: no; Reference: NLRS_41_WA_Heraklith Herafoam 130x985x590mm; ThermalTransmittance: 0.179673 kg/K/s3
Pset_ManufacturerTypeInformation - Manufacturer: Knauf Insulation B.V.

# IfcWallStandardCase: Basic Wall:NLRS_41_WA_Heraklith Herafoam 150x985x590mm, Basic Wall:NLRS_41_WA_Heraklith Herafoam 150x985x590mm:926499
In: 00 begane grond
Type - PredefinedType: STANDARD; Material: Heraklith® | Herafoam - PIR (0,0215) 100 mm, Heraklith® | Herafoam - PIR (0,0275) 40 mm, Heraklith® | Herafoam - Houtwollaag - 985x590mm 10 mm
Type - Analytical Properties - Roughness: 1; Absorptance: 0.1; Heat Transfer Coefficient (U): 0.154446; Thermal mass: 870; Thermal Resistance (R): 6.47475
Type - Construction - Function: Exterior; Wrapping at Inserts: Do not wrap; Width: 150 mm
Type - Graphics - Coarse Scale Fill Color: 0; Coarse Scale Fill Pattern: Solid fill
Type - Identity Data - Type Image: Raster image: Heraklith Herafoam.jpg; Assembly Code: 41.10; brandweerstand: n.v.t; Description: Herafoam - 150mm; DoP: 4010_HERAFOAM; email: customerservice.nl@knaufinsulation.com; geluidsabsorbtie: 0,30; Manufacturer: Knauf Insulation B.V.; Model: Heraklith® | Herafoam is een houtwolcementpaneel gecombineerd met een PIR-plaat.; NLRS_C_Code_Brandklasse: B-s1,d0; NLRS_C_content_creator: Cadix; NLRS_C_content_versie: V1.0; phone: +31(0)162-421245; product URL: https://heraklith.nl/Heraklith-houtwolcementplaten/herafoam; Type Name: NLRS_41_WA_Heraklith Herafoam 150x985x590mm; URL: www.heraklith.nl; warmteweerstand: 6,20 (m2.K/W) 6,20 (m2.K/W)
Type - Other - Category: Walls; Family Name: Basic Wall
Classification: 41.10 (Uniformat)
BaseQuantities - Height: 985 mm; Length: 590 mm; Width: 150 mm; GrossFootprintArea: 0.0885 m2; GrossSideArea: 0.58115 m2; GrossVolume: 0.0871725 m3
Constraints - Related to Mass: no; Room Bounding: yes; Base Constraint: Level: 00 begane grond; Base Extension Distance: 0 mm; Base is Attached: no; Base Offset: 0 mm; Location Line: Wall Centerline; Top Constraint: Level: 01 eerste verdieping; Top Extension Distance: 0 mm; Top is Attached: no; Top Offset: 0 mm; Unconnected Height: 985 mm
Dimensions - Area: 0.58115 m2; Length: 590 mm; Volume: 0.0871725 m3
Other - Family: Basic Wall: NLRS_41_WA_Heraklith Herafoam 150x985x590mm; Family and Type: Basic Wall: NLRS_41_WA_Heraklith Herafoam 150x985x590mm; Type: Basic Wall: NLRS_41_WA_Heraklith Herafoam 150x985x590mm; Type Id: Basic Wall: NLRS_41_WA_Heraklith Herafoam 150x985x590mm
Phasing - Phase Created: 1
Structural - Enable Analytical Model: no; Structural: no; Structural Usage: Non-bearing
Pset_WallCommon - IsExternal: yes; LoadBearing: no; ExtendToStructure: no; Reference: NLRS_41_WA_Heraklith Herafoam 150x985x590mm; ThermalTransmittance: 0.154446 kg/K/s3
Pset_ManufacturerTypeInformation - Manufacturer: Knauf Insulation B.V.

# IfcWallStandardCase: Basic Wall:NLRS_41_WA_Heraklith Herafoam 170x985x590mm, Basic Wall:NLRS_41_WA_Heraklith Herafoam 170x985x590mm:926827
In: 00 begane grond
Type - PredefinedType: STANDARD; Material: Heraklith® | Herafoam - PIR (0,0215) 120 mm, Heraklith® | Herafoam - PIR (0,0275) 40 mm, Heraklith® | Herafoam - Houtwollaag - 985x590mm 10 mm
Type - Analytical Properties - Roughness: 1; Absorptance: 0.1; Heat Transfer Coefficient (U): 0.135431; Thermal mass: 930; Thermal Resistance (R): 7.38384
Type - Construction - Function: Exterior; Wrapping at Inserts: Do not wrap; Width: 170 mm
Type - Graphics - Coarse Scale Fill Color: 0; Coarse Scale Fill Pattern: Solid fill
Type - Identity Data - Type Image: Raster image: Heraklith Herafoam.jpg; Assembly Code: 41.10; brandweerstand: n.v.t; Description: Herafoam - 170mm; DoP: 4010_HERAFOAM; email: customerservice.nl@knaufinsulation.com; geluidsabsorbtie: 0,30; Manufacturer: Knauf Insulation B.V.; Model: Heraklith® | Herafoam is een houtwolcementpaneel gecombineerd met een PIR-plaat.; NLRS_C_Code_Brandklasse: B-s1,d0; NLRS_C_content_creator: Cadix; NLRS_C_content_versie: V1.0; phone: +31(0)162-421245; product URL: https://heraklith.nl/Heraklith-houtwolcementplaten/herafoam; Type Name: NLRS_41_WA_Heraklith Herafoam 170x985x590mm; URL: www.heraklith.nl; warmteweerstand: 7,10 (m2.K/W)
Type - Other - Category: Walls; Family Name: Basic Wall
Classification: 41.10 (Uniformat)
BaseQuantities - Height: 983.54 mm; Length: 590 mm; Width: 170 mm; GrossFootprintArea: 0.1003 m2; GrossSideArea: 0.580289 m2; GrossVolume: 0.098649 m3
Constraints - Related to Mass: no; Room Bounding: yes; Base Constraint: Level: 00 begane grond; Base Extension Distance: 0 mm; Base is Attached: no; Location Line: Wall Centerline; Top Constraint: Level: 01 eerste verdieping; Top Extension Distance: 0 mm; Top is Attached: no; Top Offset: 0 mm; Base Offset: 1.46014 mm; Unconnected Height: 983.54 mm
Dimensions - Area: 0.580289 m2; Length: 590 mm; Volume: 0.098649 m3
Other - Family: Basic Wall: NLRS_41_WA_Heraklith Herafoam 170x985x590mm; Family and Type: Basic Wall: NLRS_41_WA_Heraklith Herafoam 170x985x590mm; Type: Basic Wall: NLRS_41_WA_Heraklith Herafoam 170x985x590mm; Type Id: Basic Wall: NLRS_41_WA_Heraklith Herafoam 170x985x590mm
Phasing - Phase Created: 1
Structural - Enable Analytical Model: no; Structural: no; Structural Usage: Non-bearing
Pset_WallCommon - IsExternal: yes; LoadBearing: no; ExtendToStructure: no; Reference: NLRS_41_WA_Heraklith Herafoam 170x985x590mm; ThermalTransmittance: 0.135431 kg/K/s3
Pset_ManufacturerTypeInformation - Manufacturer: Knauf Insulation B.V.

# IfcWallStandardCase: Basic Wall:NLRS_41_WA_Heraklith Herafoam 50x985x590mm, Basic Wall:NLRS_41_WA_Heraklith Herafoam 50x985x590mm:923030
In: 00 begane grond
Type - PredefinedType: STANDARD; Material: Heraklith® | Herafoam - PIR (0,0275) 40 mm, Heraklith® | Herafoam - Houtwollaag - 985x590mm 10 mm
Type - Analytical Properties - Roughness: 1; Absorptance: 0.1; Heat Transfer Coefficient (U): 0.518325; Thermal mass: 570; Thermal Resistance (R): 1.92929
Type - Construction - Function: Exterior; Wrapping at Inserts: Do not wrap; Width: 50 mm
Type - Graphics - Coarse Scale Fill Color: 0; Coarse Scale Fill Pattern: Solid fill
Type - Identity Data - Type Image: Raster image: Heraklith Herafoam.jpg; Assembly Code: 41.10; brandweerstand: n.v.t; Description: Herafoam - 50mm; DoP: 4010_HERAFOAM; email: customerservice.nl@knaufinsulation.com; geluidsabsorbtie: 0,30; Manufacturer: Knauf Insulation B.V.; Model: Heraklith® | Herafoam is een houtwolcementpaneel gecombineerd met een PIR-plaat.; NLRS_C_Code_Brandklasse: B-s1,d0; NLRS_C_content_creator: Cadix; NLRS_C_content_versie: V1.0; phone: +31(0)162-421245; product URL: https://heraklith.nl/Heraklith-houtwolcementplaten/herafoam; Type Name: NLRS_41_WA_Heraklith Herafoam 50x985x590mm; URL: www.heraklith.nl; warmteweerstand: 1,55 (m2.K/W)
Type - Other - Category: Walls; Family Name: Basic Wall
Classification: 41.10 (Uniformat)
BaseQuantities - Height: 985 mm; Length: 590 mm; Width: 50 mm; GrossFootprintArea: 0.0295 m2; GrossSideArea: 0.58115 m2; GrossVolume: 0.0290575 m3
Constraints - Related to Mass: no; Room Bounding: yes; Base Constraint: Level: 00 begane grond; Base Extension Distance: 0 mm; Base is Attached: no; Base Offset: 0 mm; Location Line: Wall Centerline; Top Constraint: Level: 01 eerste verdieping; Top Extension Distance: 0 mm; Top is Attached: no; Top Offset: 0 mm; Unconnected Height: 985 mm
Dimensions - Area: 0.58115 m2; Length: 590 mm; Volume: 0.0290575 m3
Other - Family: Basic Wall: NLRS_41_WA_Heraklith Herafoam 50x985x590mm; Family and Type: Basic Wall: NLRS_41_WA_Heraklith Herafoam 50x985x590mm; Type: Basic Wall: NLRS_41_WA_Heraklith Herafoam 50x985x590mm; Type Id: Basic Wall: NLRS_41_WA_Heraklith Herafoam 50x985x590mm
Phasing - Phase Created: 1
Structural - Enable Analytical Model: no; Structural: no; Structural Usage: Non-bearing
Pset_WallCommon - IsExternal: yes; LoadBearing: no; ExtendToStructure: no; Reference: NLRS_41_WA_Heraklith Herafoam 50x985x590mm; ThermalTransmittance: 0.518325 kg/K/s3
Pset_ManufacturerTypeInformation - Manufacturer: Knauf Insulation B.V.

# IfcWallStandardCase: Basic Wall:NLRS_41_WA_Heraklith Herafoam 80x985x590mm, Basic Wall:NLRS_41_WA_Heraklith Herafoam 80x985x590mm:925583
In: 00 begane grond
Type - PredefinedType: STANDARD; Material: Heraklith® | Herafoam - PIR (0,0222) 30 mm, Heraklith® | Herafoam - PIR (0,0275) 40 mm, Heraklith® | Herafoam - Houtwollaag - 985x590mm 10 mm
Type - Analytical Properties - Roughness: 1; Absorptance: 0.1; Heat Transfer Coefficient (U): 0.303681; Thermal mass: 660; Thermal Resistance (R): 3.29293
Type - Construction - Function: Exterior; Wrapping at Inserts: Do not wrap; Width: 80 mm
Type - Graphics - Coarse Scale Fill Color: 0; Coarse Scale Fill Pattern: Solid fill
Type - Identity Data - Type Image: Raster image: Heraklith Herafoam.jpg; Assembly Code: 41.10; brandweerstand: n.v.t; Description: Herafoam - 80mm; DoP: 4010_HERAFOAM; email: customerservice.nl@knaufinsulation.com; geluidsabsorbtie: 0,30; Manufacturer: Knauf Insulation B.V.; Model: Heraklith® | Herafoam is een houtwolcementpaneel gecombineerd met een PIR-plaat.; NLRS_C_Code_Brandklasse: B-s1,d0; NLRS_C_content_creator: Cadix; NLRS_C_content_versie: V1.0; phone: +31(0)162-421245; product URL: https://heraklith.nl/Heraklith-houtwolcementplaten/herafoam; Type Name: NLRS_41_WA_Heraklith Herafoam 80x985x590mm; URL: www.heraklith.nl; warmteweerstand: 2,90 (m2.K/W)
Type - Other - Category: Walls; Family Name: Basic Wall
Classification: 41.10 (Uniformat)
BaseQuantities - Height: 985 mm; Length: 590 mm; Width: 80 mm; GrossFootprintArea: 0.0472 m2; GrossSideArea: 0.58115 m2; GrossVolume: 0.046492 m3
Constraints - Related to Mass: no; Room Bounding: yes; Base Constraint: Level: 00 begane grond; Base Extension Distance: 0 mm; Base is Attached: no; Base Offset: 0 mm; Location Line: Wall Centerline; Top Constraint: Level: 01 eerste verdieping; Top Extension Distance: 0 mm; Top is Attached: no; Top Offset: 0 mm; Unconnected Height: 985 mm
Dimensions - Area: 0.58115 m2; Length: 590 mm; Volume: 0.046492 m3
Other - Family: Basic Wall: NLRS_41_WA_Heraklith Herafoam 80x985x590mm; Family and Type: Basic Wall: NLRS_41_WA_Heraklith Herafoam 80x985x590mm; Type: Basic Wall: NLRS_41_WA_Heraklith Herafoam 80x985x590mm; Type Id: Basic Wall: NLRS_41_WA_Heraklith Herafoam 80x985x590mm
Phasing - Phase Created: 1
Structural - Enable Analytical Model: no; Structural: no; Structural Usage: Non-bearing
Pset_WallCommon - IsExternal: yes; LoadBearing: no; ExtendToStructure: no; Reference: NLRS_41_WA_Heraklith Herafoam 80x985x590mm; ThermalTransmittance: 0.303681 kg/K/s3
Pset_ManufacturerTypeInformation - Manufacturer: Knauf Insulation B.V.

# IfcWallStandardCase: Basic Wall:NLRS_42_WA_Heraklith Herafoam 105x985x590mm, Basic Wall:NLRS_42_WA_Heraklith Herafoam 105x985x590mm:925849
In: 00 begane grond
Type - PredefinedType: STANDARD; Material: Heraklith® | Herafoam - PIR (0,0215) 55 mm, Heraklith® | Herafoam - PIR (0,0275) 40 mm, Heraklith® | Herafoam - Houtwollaag - 985x590mm 10 mm
Type - Analytical Properties - Roughness: 1; Absorptance: 0.1; Heat Transfer Coefficient (U): 0.22577; Thermal mass: 735; Thermal Resistance (R): 4.42929
Type - Construction - Function: Interior; Wrapping at Inserts: Do not wrap; Width: 105 mm
Type - Graphics - Coarse Scale Fill Color: 0; Coarse Scale Fill Pattern: Solid fill
Type - Identity Data - Type Image: Raster image: Heraklith Herafoam.jpg; Assembly Code: 42.10; brandweerstand: n.v.t; Description: Herafoam - 105mm; DoP: 4010_HERAFOAM; email: customerservice.nl@knaufinsulation.com; geluidsabsorbtie: 0,30; Manufacturer: Knauf Insulation B.V.; Model: Heraklith® | Herafoam is een houtwolcementpaneel gecombineerd met een PIR-plaat.; NLRS_C_Code_Brandklasse: B-s1,d0; NLRS_C_content_creator: Cadix; NLRS_C_content_versie: V1.0; phone: +31(0)162-421245; product URL: https://heraklith.nl/Heraklith-houtwolcementplaten/herafoam; Type Name: NLRS_42_WA_Heraklith Herafoam 105x985x590mm; URL: www.heraklith.nl; warmteweerstand: 4,10 (m2.K/W)
Type - Other - Category: Walls; Family Name: Basic Wall
Classification: 42.10 (Uniformat)
BaseQuantities - Height: 985 mm; Length: 985 mm; Width: 105 mm; GrossFootprintArea: 0.103425 m2; GrossSideArea: 0.970225 m2; GrossVolume: 0.101874 m3
Constraints - Related to Mass: no; Room Bounding: yes; Base Constraint: Level: 00 begane grond; Base Extension Distance: 0 mm; Base is Attached: no; Base Offset: 0 mm; Location Line: Wall Centerline; Top Constraint: Level: 01 eerste verdieping; Top Extension Distance: 0 mm; Top is Attached: no; Top Offset: 0 mm; Unconnected Height: 985 mm
Dimensions - Area: 0.970225 m2; Length: 985 mm; Volume: 0.101874 m3
Other - Family: Basic Wall: NLRS_42_WA_Heraklith Herafoam 105x985x590mm; Family and Type: Basic Wall: NLRS_42_WA_Heraklith Herafoam 105x985x590mm; Type: Basic Wall: NLRS_42_WA_Heraklith Herafoam 105x985x590mm; Type Id: Basic Wall: NLRS_42_WA_Heraklith Herafoam 105x985x590mm
Phasing - Phase Created: 1
Structural - Enable Analytical Model: no; Structural: no; Structural Usage: Non-bearing
Pset_WallCommon - LoadBearing: no; ExtendToStructure: no; IsExternal: no; Reference: NLRS_42_WA_Heraklith Herafoam 105x985x590mm; ThermalTransmittance: 0.22577 kg/K/s3
Pset_ManufacturerTypeInformation - Manufacturer: Knauf Insulation B.V.

# IfcWallStandardCase: Basic Wall:NLRS_42_WA_Heraklith Herafoam 130x985x590mm, Basic Wall:NLRS_42_WA_Heraklith Herafoam 130x985x590mm:926114
In: 00 begane grond
Type - PredefinedType: STANDARD; Material: Heraklith® | Herafoam - PIR (0,0215) 80 mm, Heraklith® | Herafoam - PIR (0,0275) 40 mm, Heraklith® | Herafoam - Houtwollaag - 985x590mm 10 mm
Type - Analytical Properties - Roughness: 1; Absorptance: 0.1; Heat Transfer Coefficient (U): 0.179673; Thermal mass: 810; Thermal Resistance (R): 5.56566
Type - Construction - Function: Interior; Wrapping at Inserts: Do not wrap; Width: 130 mm
Type - Graphics - Coarse Scale Fill Color: 0; Coarse Scale Fill Pattern: Solid fill
Type - Identity Data - Type Image: Raster image: Heraklith Herafoam.jpg; Assembly Code: 42.10; brandweerstand: n.v.t; Description: Herafoam - 130mm; DoP: 4010_HERAFOAM; email: customerservice.nl@knaufinsulation.com; geluidsabsorbtie: 0,30; Manufacturer: Knauf Insulation B.V.; Model: Heraklith® | Herafoam is een houtwolcementpaneel gecombineerd met een PIR-plaat.; NLRS_C_Code_Brandklasse: B-s1,d0; NLRS_C_content_creator: Cadix; NLRS_C_content_versie: V1.0; phone: +31(0)162-421245; product URL: https://heraklith.nl/Heraklith-houtwolcementplaten/herafoam; Type Name: NLRS_42_WA_Heraklith Herafoam 130x985x590mm; URL: www.heraklith.nl; warmteweerstand: 5,25 (m2.K/W)
Type - Other - Category: Walls; Family Name: Basic Wall
Classification: 42.10 (Uniformat)
BaseQuantities - Height: 985 mm; Length: 945 mm; Width: 130 mm; GrossFootprintArea: 0.12285 m2; GrossSideArea: 0.930825 m2; GrossVolume: 0.121007 m3
Constraints - Related to Mass: no; Room Bounding: yes; Base Constraint: Level: 00 begane grond; Base Extension Distance: 0 mm; Base is Attached: no; Base Offset: 0 mm; Location Line: Wall Centerline; Top Constraint: Level: 01 eerste verdieping; Top Extension Distance: 0 mm; Top is Attached: no; Top Offset: 0 mm; Unconnected Height: 985 mm
Dimensions - Area: 0.930825 m2; Length: 1010 mm; Volume: 0.121007 m3
Other - Family: Basic Wall: NLRS_42_WA_Heraklith Herafoam 130x985x590mm; Family and Type: Basic Wall: NLRS_42_WA_Heraklith Herafoam 130x985x590mm; Type: Basic Wall: NLRS_42_WA_Heraklith Herafoam 130x985x590mm; Type Id: Basic Wall: NLRS_42_WA_Heraklith Herafoam 130x985x590mm
Phasing - Phase Created: 1
Structural - Enable Analytical Model: no; Structural: no; Structural Usage: Non-bearing
Pset_WallCommon - LoadBearing: no; ExtendToStructure: no; IsExternal: no; Reference: NLRS_42_WA_Heraklith Herafoam 130x985x590mm; ThermalTransmittance: 0.179673 kg/K/s3
Pset_ManufacturerTypeInformation - Manufacturer: Knauf Insulation B.V.

# IfcWallStandardCase: Basic Wall:NLRS_42_WA_Heraklith Herafoam 150x985x590mm, Basic Wall:NLRS_42_WA_Heraklith Herafoam 150x985x590mm:926746
In: 00 begane grond
Type - PredefinedType: STANDARD; Material: Heraklith® | Herafoam - PIR (0,0215) 100 mm, Heraklith® | Herafoam - PIR (0,0275) 40 mm, Heraklith® | Herafoam - Houtwollaag - 985x590mm 10 mm
Type - Analytical Properties - Roughness: 1; Absorptance: 0.1; Heat Transfer Coefficient (U): 0.154446; Thermal mass: 870; Thermal Resistance (R): 6.47475
Type - Construction - Function: Interior; Wrapping at Inserts: Do not wrap; Width: 150 mm
Type - Graphics - Coarse Scale Fill Color: 0; Coarse Scale Fill Pattern: Solid fill
Type - Identity Data - Type Image: Raster image: Heraklith Herafoam.jpg; Assembly Code: 42.10; brandweerstand: n.v.t; Description: Herafoam - 150mm; DoP: 4010_HERAFOAM; email: customerservice.nl@knaufinsulation.com; geluidsabsorbtie: 0,30; Manufacturer: Knauf Insulation B.V.; Model: Heraklith® | Herafoam is een houtwolcementpaneel gecombineerd met een PIR-plaat.; NLRS_C_Code_Brandklasse: B-s1,d0; NLRS_C_content_creator: Cadix; NLRS_C_content_versie: V1.0; phone: +31(0)162-421245; product URL: https://heraklith.nl/Heraklith-houtwolcementplaten/herafoam; Type Name: NLRS_42_WA_Heraklith Herafoam 150x985x590mm; URL: www.heraklith.nl; warmteweerstand: 6,20 (m2.K/W)
Type - Other - Category: Walls; Family Name: Basic Wall
Classification: 42.10 (Uniformat)
BaseQuantities - Height: 985 mm; Length: 935 mm; Width: 150 mm; GrossFootprintArea: 0.14025 m2; GrossSideArea: 0.920975 m2; GrossVolume: 0.138146 m3
Constraints - Related to Mass: no; Room Bounding: yes; Base Constraint: Level: 00 begane grond; Base Extension Distance: 0 mm; Base is Attached: no; Base Offset: 0 mm; Location Line: Wall Centerline; Top Constraint: Level: 01 eerste verdieping; Top Extension Distance: 0 mm; Top is Attached: no; Top Offset: 0 mm; Unconnected Height: 985 mm
Dimensions - Area: 0.920975 m2; Length: 1010 mm; Volume: 0.138146 m3
Other - Family: Basic Wall: NLRS_42_WA_Heraklith Herafoam 150x985x590mm; Family and Type: Basic Wall: NLRS_42_WA_Heraklith Herafoam 150x985x590mm; Type: Basic Wall: NLRS_42_WA_Heraklith Herafoam 150x985x590mm; Type Id: Basic Wall: NLRS_42_WA_Heraklith Herafoam 150x985x590mm
Phasing - Phase Created: 1
Structural - Enable Analytical Model: no; Structural: no; Structural Usage: Non-bearing
Pset_WallCommon - LoadBearing: no; ExtendToStructure: no; IsExternal: no; Reference: NLRS_42_WA_Heraklith Herafoam 150x985x590mm; ThermalTransmittance: 0.154446 kg/K/s3
Pset_ManufacturerTypeInformation - Manufacturer: Knauf Insulation B.V.

# IfcWallStandardCase: Basic Wall:NLRS_42_WA_Heraklith Herafoam 170x985x590mm, Basic Wall:NLRS_42_WA_Heraklith Herafoam 170x985x590mm:926985
In: 00 begane grond
Type - PredefinedType: STANDARD; Material: Heraklith® | Herafoam - PIR (0,0215) 120 mm, Heraklith® | Herafoam - PIR (0,0275) 40 mm, Heraklith® | Herafoam - Houtwollaag - 985x590mm 10 mm
Type - Analytical Properties - Roughness: 1; Absorptance: 0.1; Heat Transfer Coefficient (U): 0.135431; Thermal mass: 930; Thermal Resistance (R): 7.38384
Type - Construction - Function: Interior; Wrapping at Inserts: Do not wrap; Width: 170 mm
Type - Graphics - Coarse Scale Fill Color: 0; Coarse Scale Fill Pattern: Solid fill
Type - Identity Data - Type Image: Raster image: Heraklith Herafoam.jpg; Assembly Code: 42.10; brandweerstand: n.v.t; Description: Herafoam - 170mm; DoP: 4010_HERAFOAM; email: customerservice.nl@knaufinsulation.com; geluidsabsorbtie: 0,30; Manufacturer: Knauf Insulation B.V.; Model: Heraklith® | Herafoam is een houtwolcementpaneel gecombineerd met een PIR-plaat.; NLRS_C_Code_Brandklasse: B-s1,d0; NLRS_C_content_creator: Cadix; NLRS_C_content_versie: V1.0; phone: +31(0)162-421245; product URL: https://heraklith.nl/Heraklith-houtwolcementplaten/herafoam; Type Name: NLRS_42_WA_Heraklith Herafoam 170x985x590mm; URL: www.heraklith.nl; warmteweerstand: 7,10 (m2.K/W)
Type - Other - Category: Walls; Family Name: Basic Wall
Classification: 42.10 (Uniformat)
BaseQuantities - Height: 985 mm; Length: 925 mm; Width: 170 mm; GrossFootprintArea: 0.15725 m2; GrossSideArea: 0.911125 m2; GrossVolume: 0.154891 m3
Constraints - Related to Mass: no; Room Bounding: yes; Base Constraint: Level: 00 begane grond; Base Extension Distance: 0 mm; Base is Attached: no; Base Offset: 0 mm; Location Line: Wall Centerline; Top Constraint: Level: 01 eerste verdieping; Top Extension Distance: 0 mm; Top is Attached: no; Top Offset: 0 mm; Unconnected Height: 985 mm
Dimensions - Area: 0.911125 m2; Length: 1010 mm; Volume: 0.154891 m3
Other - Family: Basic Wall: NLRS_42_WA_Heraklith Herafoam 170x985x590mm; Family and Type: Basic Wall: NLRS_42_WA_Heraklith Herafoam 170x985x590mm; Type: Basic Wall: NLRS_42_WA_Heraklith Herafoam 170x985x590mm; Type Id: Basic Wall: NLRS_42_WA_Heraklith Herafoam 170x985x590mm
Phasing - Phase Created: 1
Structural - Enable Analytical Model: no; Structural: no; Structural Usage: Non-bearing
Pset_WallCommon - LoadBearing: no; ExtendToStructure: no; IsExternal: no; Reference: NLRS_42_WA_Heraklith Herafoam 170x985x590mm; ThermalTransmittance: 0.135431 kg/K/s3
Pset_ManufacturerTypeInformation - Manufacturer: Knauf Insulation B.V.

# IfcWallStandardCase: Basic Wall:NLRS_42_WA_Heraklith Herafoam 50x985x590mm, Basic Wall:NLRS_42_WA_Heraklith Herafoam 50x985x590mm:922774
In: 00 begane grond
Type - PredefinedType: STANDARD; Material: Heraklith® | Herafoam - PIR (0,0275) 40 mm, Heraklith® | Herafoam - Houtwollaag - 985x590mm 10 mm
Type - Analytical Properties - Roughness: 1; Absorptance: 0.1; Heat Transfer Coefficient (U): 0.518325; Thermal mass: 570; Thermal Resistance (R): 1.92929
Type - Construction - Function: Interior; Width: 50 mm; Wrapping at Inserts: Do not wrap
Type - Graphics - Coarse Scale Fill Color: 0; Coarse Scale Fill Pattern: Solid fill
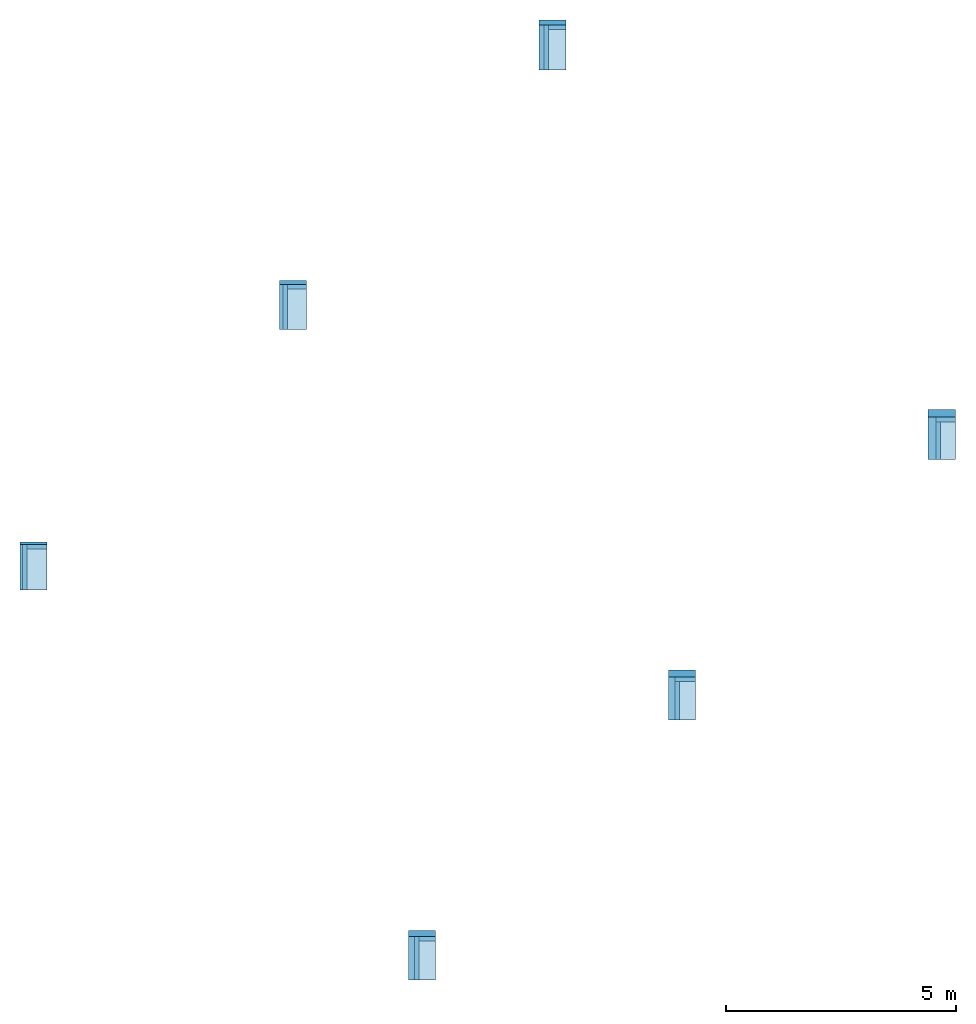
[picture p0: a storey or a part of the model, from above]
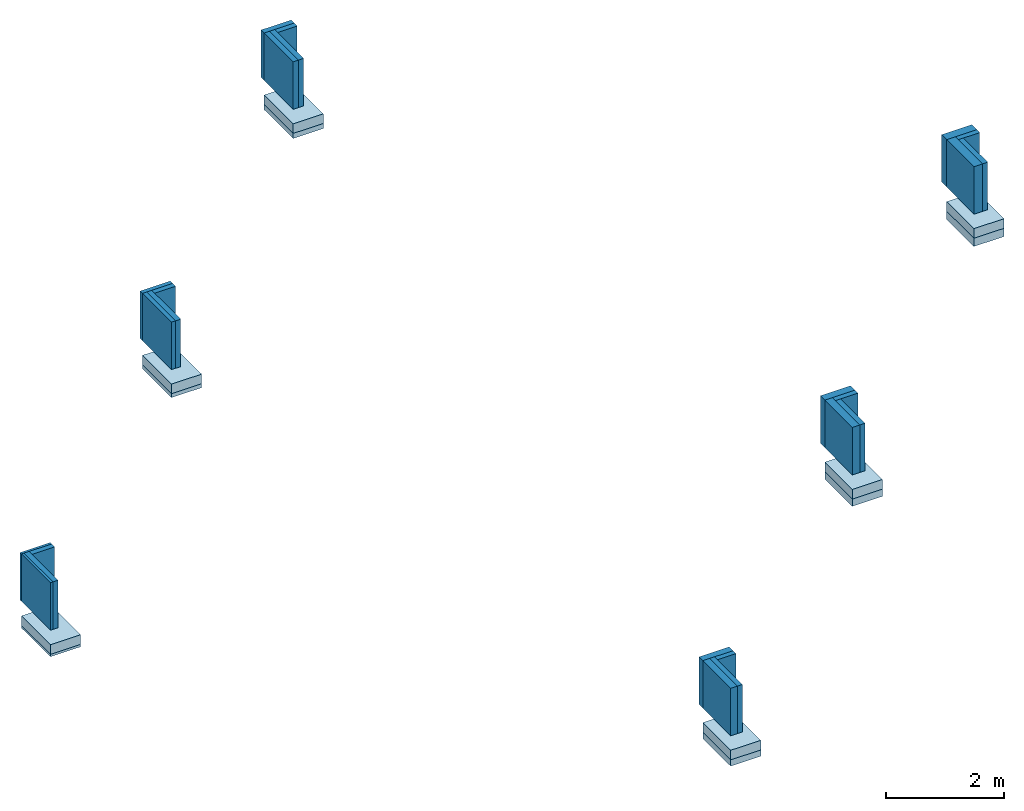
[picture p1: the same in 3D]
Properties of the parts of a building model (IFC2X3), part 2 of 2

# IfcWallStandardCase: Basic Wall:NLRS_42_WA_Heraklith Herafoam 50x985x590mm, Basic Wall:NLRS_42_WA_Heraklith Herafoam 50x985x590mm:922774
Type - Identity Data - Type Image: Raster image: Heraklith Herafoam.jpg; Assembly Code: 42.10; brandweerstand: n.v.t; Description: Herafoam - 50mm; DoP: 4010_HERAFOAM; email: customerservice.nl@knaufinsulation.com; geluidsabsorbtie: 0,30; Manufacturer: Knauf Insulation B.V.; Model: Heraklith® | Herafoam is een houtwolcementpaneel gecombineerd met een PIR-plaat.; NLRS_C_Code_Brandklasse: B-s1,d0; NLRS_C_content_creator: Cadix; NLRS_C_content_versie: V1.0; phone: +31(0)162-421245; product URL: https://heraklith.nl/Heraklith-houtwolcementplaten/herafoam; Type Name: NLRS_42_WA_Heraklith Herafoam 50x985x590mm; URL: www.heraklith.nl; warmteweerstand: 1,55 (m2.K/W)
Type - Other - Category: Walls; Family Name: Basic Wall
Classification: 42.10 (Uniformat)
BaseQuantities - Height: 985 mm; Length: 985 mm; Width: 50 mm; GrossFootprintArea: 0.04925 m2; GrossSideArea: 0.970225 m2; GrossVolume: 0.0485113 m3
Constraints - Related to Mass: no; Room Bounding: yes; Base Constraint: Level: 00 begane grond; Base Extension Distance: 0 mm; Base is Attached: no; Base Offset: 0 mm; Location Line: Wall Centerline; Top Constraint: Level: 01 eerste verdieping; Top Extension Distance: 0 mm; Top is Attached: no; Top Offset: 0 mm; Unconnected Height: 985 mm
Dimensions - Area: 0.970225 m2; Length: 1010 mm; Volume: 0.0485113 m3
Other - Family: Basic Wall: NLRS_42_WA_Heraklith Herafoam 50x985x590mm; Family and Type: Basic Wall: NLRS_42_WA_Heraklith Herafoam 50x985x590mm; Type: Basic Wall: NLRS_42_WA_Heraklith Herafoam 50x985x590mm; Type Id: Basic Wall: NLRS_42_WA_Heraklith Herafoam 50x985x590mm
Phasing - Phase Created: 1
Structural - Enable Analytical Model: no; Structural: no; Structural Usage: Non-bearing
Pset_WallCommon - Reference: NLRS_42_WA_Heraklith Herafoam 50x985x590mm; LoadBearing: no; ExtendToStructure: no; IsExternal: no; ThermalTransmittance: 0.518325 kg/K/s3
Pset_ManufacturerTypeInformation - Manufacturer: Knauf Insulation B.V.

# IfcWallStandardCase: Basic Wall:NLRS_42_WA_Heraklith Herafoam 80x985x590mm, Basic Wall:NLRS_42_WA_Heraklith Herafoam 80x985x590mm:925193
In: 00 begane grond
Type - PredefinedType: STANDARD; Material: Heraklith® | Herafoam - PIR (0,0222) 30 mm, Heraklith® | Herafoam - PIR (0,0275) 40 mm, Heraklith® | Herafoam - Houtwollaag - 985x590mm 10 mm
Type - Analytical Properties - Roughness: 1; Absorptance: 0.1; Heat Transfer Coefficient (U): 0.303681; Thermal mass: 660; Thermal Resistance (R): 3.29293
Type - Construction - Function: Interior; Wrapping at Inserts: Do not wrap; Width: 80 mm
Type - Graphics - Coarse Scale Fill Color: 0; Coarse Scale Fill Pattern: Solid fill
Type - Identity Data - Type Image: Raster image: Heraklith Herafoam.jpg; Assembly Code: 42.10; brandweerstand: n.v.t; Description: Herafoam - 80mm; DoP: 4010_HERAFOAM; email: customerservice.nl@knaufinsulation.com; geluidsabsorbtie: 0,30; Manufacturer: Knauf Insulation B.V.; Model: Heraklith® | Herafoam is een houtwolcementpaneel gecombineerd met een PIR-plaat.; NLRS_C_Code_Brandklasse: B-s1,d0; NLRS_C_content_creator: Cadix; NLRS_C_content_versie: V1.0; phone: +31(0)162-421245; product URL: https://heraklith.nl/Heraklith-houtwolcementplaten/herafoam; Type Name: NLRS_42_WA_Heraklith Herafoam 80x985x590mm; URL: www.heraklith.nl; warmteweerstand: 2,90 (m2.K/W)
Type - Other - Category: Walls; Family Name: Basic Wall
Classification: 42.10 (Uniformat)
BaseQuantities - Height: 985 mm; Length: 985 mm; Width: 80 mm; GrossFootprintArea: 0.0788 m2; GrossSideArea: 0.970225 m2; GrossVolume: 0.077618 m3
Constraints - Related to Mass: no; Room Bounding: yes; Base Constraint: Level: 00 begane grond; Base Extension Distance: 0 mm; Base is Attached: no; Base Offset: 0 mm; Location Line: Wall Centerline; Top Constraint: Level: 01 eerste verdieping; Top Extension Distance: 0 mm; Top is Attached: no; Top Offset: 0 mm; Unconnected Height: 985 mm
Dimensions - Area: 0.970225 m2; Length: 985 mm; Volume: 0.077618 m3
Other - Family: Basic Wall: NLRS_42_WA_Heraklith Herafoam 80x985x590mm; Family and Type: Basic Wall: NLRS_42_WA_Heraklith Herafoam 80x985x590mm; Type: Basic Wall: NLRS_42_WA_Heraklith Herafoam 80x985x590mm; Type Id: Basic Wall: NLRS_42_WA_Heraklith Herafoam 80x985x590mm
Phasing - Phase Created: 1
Structural - Enable Analytical Model: no; Structural: no; Structural Usage: Non-bearing
Pset_WallCommon - LoadBearing: no; ExtendToStructure: no; IsExternal: no; Reference: NLRS_42_WA_Heraklith Herafoam 80x985x590mm; ThermalTransmittance: 0.303681 kg/K/s3
Pset_ManufacturerTypeInformation - Manufacturer: Knauf Insulation B.V.
